VERSION 5.7 ;
  NOWIREEXTENSIONATPIN ON ;
  DIVIDERCHAR "/" ;
  BUSBITCHARS "[]" ;
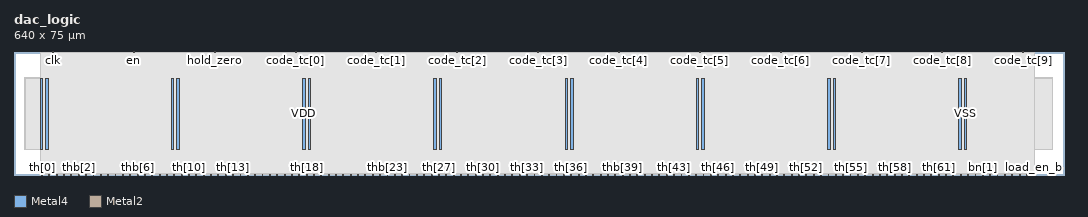
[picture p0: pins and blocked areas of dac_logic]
MACRO dac_logic
  CLASS BLOCK ;
  FOREIGN dac_logic ;
  ORIGIN 0.000 0.000 ;
  SIZE 640.000 BY 75.000 ;
  PIN VDD
    DIRECTION INOUT ;
    USE POWER ;
    PORT
      LAYER Metal4 ;
        RECT 15.920 15.380 17.520 59.100 ;
    END
    PORT
      LAYER Metal4 ;
        RECT 95.920 15.380 97.520 59.100 ;
    END
    PORT
      LAYER Metal4 ;
        RECT 175.920 15.380 177.520 59.100 ;
    END
    PORT
      LAYER Metal4 ;
        RECT 255.920 15.380 257.520 59.100 ;
    END
    PORT
      LAYER Metal4 ;
        RECT 335.920 15.380 337.520 59.100 ;
    END
    PORT
      LAYER Metal4 ;
        RECT 415.920 15.380 417.520 59.100 ;
    END
    PORT
      LAYER Metal4 ;
        RECT 495.920 15.380 497.520 59.100 ;
    END
    PORT
      LAYER Metal4 ;
        RECT 575.920 15.380 577.520 59.100 ;
    END
  END VDD
  PIN VSS
    DIRECTION INOUT ;
    USE GROUND ;
    PORT
      LAYER Metal4 ;
        RECT 19.220 15.380 20.820 59.100 ;
    END
    PORT
      LAYER Metal4 ;
        RECT 99.220 15.380 100.820 59.100 ;
    END
    PORT
      LAYER Metal4 ;
        RECT 179.220 15.380 180.820 59.100 ;
    END
    PORT
      LAYER Metal4 ;
        RECT 259.220 15.380 260.820 59.100 ;
    END
    PORT
      LAYER Metal4 ;
        RECT 339.220 15.380 340.820 59.100 ;
    END
    PORT
      LAYER Metal4 ;
        RECT 419.220 15.380 420.820 59.100 ;
    END
    PORT
      LAYER Metal4 ;
        RECT 499.220 15.380 500.820 59.100 ;
    END
    PORT
      LAYER Metal4 ;
        RECT 579.220 15.380 580.820 59.100 ;
    END
  END VSS
  PIN bn[0]
    DIRECTION OUTPUT ;
    USE SIGNAL ;
    ANTENNAGATEAREA 0.898000 ;
    ANTENNADIFFAREA 0.893200 ;
    PORT
      LAYER Metal2 ;
        RECT 581.280 0.000 581.840 0.560 ;
    END
  END bn[0]
  PIN bn[1]
    DIRECTION OUTPUT ;
    USE SIGNAL ;
    ANTENNAGATEAREA 0.898000 ;
    ANTENNADIFFAREA 0.893200 ;
    PORT
      LAYER Metal2 ;
        RECT 590.240 0.000 590.800 0.560 ;
    END
  END bn[1]
  PIN bn[2]
    DIRECTION OUTPUT ;
    USE SIGNAL ;
    ANTENNAGATEAREA 0.898000 ;
    ANTENNADIFFAREA 0.893200 ;
    PORT
      LAYER Metal2 ;
        RECT 599.200 0.000 599.760 0.560 ;
    END
  END bn[2]
  PIN bn[3]
    DIRECTION OUTPUT ;
    USE SIGNAL ;
    ANTENNAGATEAREA 0.898000 ;
    ANTENNADIFFAREA 0.893200 ;
    PORT
      LAYER Metal2 ;
        RECT 608.160 0.000 608.720 0.560 ;
    END
  END bn[3]
  PIN bnb[0]
    DIRECTION OUTPUT ;
    USE SIGNAL ;
    ANTENNADIFFAREA 0.748000 ;
    PORT
      LAYER Metal2 ;
        RECT 585.760 0.000 586.320 0.560 ;
    END
  END bnb[0]
  PIN bnb[1]
    DIRECTION OUTPUT ;
    USE SIGNAL ;
    ANTENNADIFFAREA 0.748000 ;
    PORT
      LAYER Metal2 ;
        RECT 594.720 0.000 595.280 0.560 ;
    END
  END bnb[1]
  PIN bnb[2]
    DIRECTION OUTPUT ;
    USE SIGNAL ;
    ANTENNADIFFAREA 0.748000 ;
    PORT
      LAYER Metal2 ;
        RECT 603.680 0.000 604.240 0.560 ;
    END
  END bnb[2]
  PIN bnb[3]
    DIRECTION OUTPUT ;
    USE SIGNAL ;
    ANTENNADIFFAREA 0.748000 ;
    PORT
      LAYER Metal2 ;
        RECT 612.640 0.000 613.200 0.560 ;
    END
  END bnb[3]
  PIN clk
    DIRECTION INPUT ;
    USE SIGNAL ;
    ANTENNAGATEAREA 4.738000 ;
    PORT
      LAYER Metal2 ;
        RECT 23.520 74.440 24.080 75.000 ;
    END
  END clk
  PIN code_tc[0]
    DIRECTION INPUT ;
    USE SIGNAL ;
    ANTENNAGATEAREA 0.519000 ;
    ANTENNADIFFAREA 0.410400 ;
    PORT
      LAYER Metal2 ;
        RECT 171.360 74.440 171.920 75.000 ;
    END
  END code_tc[0]
  PIN code_tc[1]
    DIRECTION INPUT ;
    USE SIGNAL ;
    ANTENNAGATEAREA 0.519000 ;
    ANTENNADIFFAREA 0.410400 ;
    PORT
      LAYER Metal2 ;
        RECT 220.640 74.440 221.200 75.000 ;
    END
  END code_tc[1]
  PIN code_tc[2]
    DIRECTION INPUT ;
    USE SIGNAL ;
    ANTENNAGATEAREA 0.519000 ;
    PORT
      LAYER Metal2 ;
        RECT 269.920 74.440 270.480 75.000 ;
    END
  END code_tc[2]
  PIN code_tc[3]
    DIRECTION INPUT ;
    USE SIGNAL ;
    ANTENNAGATEAREA 0.519000 ;
    PORT
      LAYER Metal2 ;
        RECT 319.200 74.440 319.760 75.000 ;
    END
  END code_tc[3]
  PIN code_tc[4]
    DIRECTION INPUT ;
    USE SIGNAL ;
    ANTENNAGATEAREA 0.519000 ;
    PORT
      LAYER Metal2 ;
        RECT 368.480 74.440 369.040 75.000 ;
    END
  END code_tc[4]
  PIN code_tc[5]
    DIRECTION INPUT ;
    USE SIGNAL ;
    ANTENNAGATEAREA 0.519000 ;
    PORT
      LAYER Metal2 ;
        RECT 417.760 74.440 418.320 75.000 ;
    END
  END code_tc[5]
  PIN code_tc[6]
    DIRECTION INPUT ;
    USE SIGNAL ;
    ANTENNAGATEAREA 0.519000 ;
    PORT
      LAYER Metal2 ;
        RECT 467.040 74.440 467.600 75.000 ;
    END
  END code_tc[6]
  PIN code_tc[7]
    DIRECTION INPUT ;
    USE SIGNAL ;
    ANTENNAGATEAREA 0.519000 ;
    PORT
      LAYER Metal2 ;
        RECT 516.320 74.440 516.880 75.000 ;
    END
  END code_tc[7]
  PIN code_tc[8]
    DIRECTION INPUT ;
    USE SIGNAL ;
    ANTENNAGATEAREA 0.519000 ;
    PORT
      LAYER Metal2 ;
        RECT 565.600 74.440 566.160 75.000 ;
    END
  END code_tc[8]
  PIN code_tc[9]
    DIRECTION INPUT ;
    USE SIGNAL ;
    ANTENNAGATEAREA 1.057000 ;
    PORT
      LAYER Metal2 ;
        RECT 614.880 74.440 615.440 75.000 ;
    END
  END code_tc[9]
  PIN en
    DIRECTION INPUT ;
    USE SIGNAL ;
    ANTENNAGATEAREA 103.009995 ;
    PORT
      LAYER Metal2 ;
        RECT 72.800 74.440 73.360 75.000 ;
    END
  END en
  PIN hold_zero
    DIRECTION INPUT ;
    USE SIGNAL ;
    ANTENNAGATEAREA 0.898000 ;
    PORT
      LAYER Metal2 ;
        RECT 122.080 74.440 122.640 75.000 ;
    END
  END hold_zero
  PIN load_en_b
    DIRECTION OUTPUT ;
    USE SIGNAL ;
    ANTENNADIFFAREA 0.748000 ;
    PORT
      LAYER Metal2 ;
        RECT 621.600 0.000 622.160 0.560 ;
    END
  END load_en_b
  PIN out_en
    DIRECTION OUTPUT ;
    USE SIGNAL ;
    ANTENNADIFFAREA 0.897600 ;
    PORT
      LAYER Metal2 ;
        RECT 617.120 0.000 617.680 0.560 ;
    END
  END out_en
  PIN th[0]
    DIRECTION OUTPUT ;
    USE SIGNAL ;
    ANTENNAGATEAREA 0.898000 ;
    ANTENNADIFFAREA 0.893200 ;
    PORT
      LAYER Metal2 ;
        RECT 16.800 0.000 17.360 0.560 ;
    END
  END th[0]
  PIN th[10]
    DIRECTION OUTPUT ;
    USE SIGNAL ;
    ANTENNAGATEAREA 0.898000 ;
    ANTENNADIFFAREA 0.893200 ;
    PORT
      LAYER Metal2 ;
        RECT 106.400 0.000 106.960 0.560 ;
    END
  END th[10]
  PIN th[11]
    DIRECTION OUTPUT ;
    USE SIGNAL ;
    ANTENNAGATEAREA 0.898000 ;
    ANTENNADIFFAREA 0.893200 ;
    PORT
      LAYER Metal2 ;
        RECT 115.360 0.000 115.920 0.560 ;
    END
  END th[11]
  PIN th[12]
    DIRECTION OUTPUT ;
    USE SIGNAL ;
    ANTENNAGATEAREA 0.898000 ;
    ANTENNADIFFAREA 0.893200 ;
    PORT
      LAYER Metal2 ;
        RECT 124.320 0.000 124.880 0.560 ;
    END
  END th[12]
  PIN th[13]
    DIRECTION OUTPUT ;
    USE SIGNAL ;
    ANTENNAGATEAREA 0.898000 ;
    ANTENNADIFFAREA 0.893200 ;
    PORT
      LAYER Metal2 ;
        RECT 133.280 0.000 133.840 0.560 ;
    END
  END th[13]
  PIN th[14]
    DIRECTION OUTPUT ;
    USE SIGNAL ;
    ANTENNAGATEAREA 0.898000 ;
    ANTENNADIFFAREA 0.893200 ;
    PORT
      LAYER Metal2 ;
        RECT 142.240 0.000 142.800 0.560 ;
    END
  END th[14]
  PIN th[15]
    DIRECTION OUTPUT ;
    USE SIGNAL ;
    ANTENNAGATEAREA 0.898000 ;
    ANTENNADIFFAREA 0.893200 ;
    PORT
      LAYER Metal2 ;
        RECT 151.200 0.000 151.760 0.560 ;
    END
  END th[15]
  PIN th[16]
    DIRECTION OUTPUT ;
    USE SIGNAL ;
    ANTENNAGATEAREA 0.898000 ;
    ANTENNADIFFAREA 0.893200 ;
    PORT
      LAYER Metal2 ;
        RECT 160.160 0.000 160.720 0.560 ;
    END
  END th[16]
  PIN th[17]
    DIRECTION OUTPUT ;
    USE SIGNAL ;
    ANTENNAGATEAREA 0.898000 ;
    ANTENNADIFFAREA 0.893200 ;
    PORT
      LAYER Metal2 ;
        RECT 169.120 0.000 169.680 0.560 ;
    END
  END th[17]
  PIN th[18]
    DIRECTION OUTPUT ;
    USE SIGNAL ;
    ANTENNAGATEAREA 0.898000 ;
    ANTENNADIFFAREA 0.893200 ;
    PORT
      LAYER Metal2 ;
        RECT 178.080 0.000 178.640 0.560 ;
    END
  END th[18]
  PIN th[19]
    DIRECTION OUTPUT ;
    USE SIGNAL ;
    ANTENNAGATEAREA 0.898000 ;
    ANTENNADIFFAREA 0.893200 ;
    PORT
      LAYER Metal2 ;
        RECT 187.040 0.000 187.600 0.560 ;
    END
  END th[19]
  PIN th[1]
    DIRECTION OUTPUT ;
    USE SIGNAL ;
    ANTENNAGATEAREA 0.898000 ;
    ANTENNADIFFAREA 0.893200 ;
    PORT
      LAYER Metal2 ;
        RECT 25.760 0.000 26.320 0.560 ;
    END
  END th[1]
  PIN th[20]
    DIRECTION OUTPUT ;
    USE SIGNAL ;
    ANTENNAGATEAREA 0.898000 ;
    ANTENNADIFFAREA 0.893200 ;
    PORT
      LAYER Metal2 ;
        RECT 196.000 0.000 196.560 0.560 ;
    END
  END th[20]
  PIN th[21]
    DIRECTION OUTPUT ;
    USE SIGNAL ;
    ANTENNAGATEAREA 0.898000 ;
    ANTENNADIFFAREA 0.893200 ;
    PORT
      LAYER Metal2 ;
        RECT 204.960 0.000 205.520 0.560 ;
    END
  END th[21]
  PIN th[22]
    DIRECTION OUTPUT ;
    USE SIGNAL ;
    ANTENNAGATEAREA 0.898000 ;
    ANTENNADIFFAREA 0.893200 ;
    PORT
      LAYER Metal2 ;
        RECT 213.920 0.000 214.480 0.560 ;
    END
  END th[22]
  PIN th[23]
    DIRECTION OUTPUT ;
    USE SIGNAL ;
    ANTENNAGATEAREA 0.898000 ;
    ANTENNADIFFAREA 0.893200 ;
    PORT
      LAYER Metal2 ;
        RECT 222.880 0.000 223.440 0.560 ;
    END
  END th[23]
  PIN th[24]
    DIRECTION OUTPUT ;
    USE SIGNAL ;
    ANTENNAGATEAREA 0.898000 ;
    ANTENNADIFFAREA 0.893200 ;
    PORT
      LAYER Metal2 ;
        RECT 231.840 0.000 232.400 0.560 ;
    END
  END th[24]
  PIN th[25]
    DIRECTION OUTPUT ;
    USE SIGNAL ;
    ANTENNAGATEAREA 0.898000 ;
    ANTENNADIFFAREA 0.893200 ;
    PORT
      LAYER Metal2 ;
        RECT 240.800 0.000 241.360 0.560 ;
    END
  END th[25]
  PIN th[26]
    DIRECTION OUTPUT ;
    USE SIGNAL ;
    ANTENNAGATEAREA 0.898000 ;
    ANTENNADIFFAREA 0.893200 ;
    PORT
      LAYER Metal2 ;
        RECT 249.760 0.000 250.320 0.560 ;
    END
  END th[26]
  PIN th[27]
    DIRECTION OUTPUT ;
    USE SIGNAL ;
    ANTENNAGATEAREA 0.898000 ;
    ANTENNADIFFAREA 0.893200 ;
    PORT
      LAYER Metal2 ;
        RECT 258.720 0.000 259.280 0.560 ;
    END
  END th[27]
  PIN th[28]
    DIRECTION OUTPUT ;
    USE SIGNAL ;
    ANTENNAGATEAREA 0.898000 ;
    ANTENNADIFFAREA 0.893200 ;
    PORT
      LAYER Metal2 ;
        RECT 267.680 0.000 268.240 0.560 ;
    END
  END th[28]
  PIN th[29]
    DIRECTION OUTPUT ;
    USE SIGNAL ;
    ANTENNAGATEAREA 0.898000 ;
    ANTENNADIFFAREA 0.893200 ;
    PORT
      LAYER Metal2 ;
        RECT 276.640 0.000 277.200 0.560 ;
    END
  END th[29]
  PIN th[2]
    DIRECTION OUTPUT ;
    USE SIGNAL ;
    ANTENNAGATEAREA 0.898000 ;
    ANTENNADIFFAREA 0.893200 ;
    PORT
      LAYER Metal2 ;
        RECT 34.720 0.000 35.280 0.560 ;
    END
  END th[2]
  PIN th[30]
    DIRECTION OUTPUT ;
    USE SIGNAL ;
    ANTENNAGATEAREA 0.898000 ;
    ANTENNADIFFAREA 0.893200 ;
    PORT
      LAYER Metal2 ;
        RECT 285.600 0.000 286.160 0.560 ;
    END
  END th[30]
  PIN th[31]
    DIRECTION OUTPUT ;
    USE SIGNAL ;
    ANTENNAGATEAREA 0.898000 ;
    ANTENNADIFFAREA 0.893200 ;
    PORT
      LAYER Metal2 ;
        RECT 294.560 0.000 295.120 0.560 ;
    END
  END th[31]
  PIN th[32]
    DIRECTION OUTPUT ;
    USE SIGNAL ;
    ANTENNAGATEAREA 0.898000 ;
    ANTENNADIFFAREA 0.893200 ;
    PORT
      LAYER Metal2 ;
        RECT 303.520 0.000 304.080 0.560 ;
    END
  END th[32]
  PIN th[33]
    DIRECTION OUTPUT ;
    USE SIGNAL ;
    ANTENNAGATEAREA 0.898000 ;
    ANTENNADIFFAREA 0.893200 ;
    PORT
      LAYER Metal2 ;
        RECT 312.480 0.000 313.040 0.560 ;
    END
  END th[33]
  PIN th[34]
    DIRECTION OUTPUT ;
    USE SIGNAL ;
    ANTENNAGATEAREA 0.898000 ;
    ANTENNADIFFAREA 0.893200 ;
    PORT
      LAYER Metal2 ;
        RECT 321.440 0.000 322.000 0.560 ;
    END
  END th[34]
  PIN th[35]
    DIRECTION OUTPUT ;
    USE SIGNAL ;
    ANTENNAGATEAREA 0.898000 ;
    ANTENNADIFFAREA 0.893200 ;
    PORT
      LAYER Metal2 ;
        RECT 330.400 0.000 330.960 0.560 ;
    END
  END th[35]
  PIN th[36]
    DIRECTION OUTPUT ;
    USE SIGNAL ;
    ANTENNAGATEAREA 0.898000 ;
    ANTENNADIFFAREA 0.893200 ;
    PORT
      LAYER Metal2 ;
        RECT 339.360 0.000 339.920 0.560 ;
    END
  END th[36]
  PIN th[37]
    DIRECTION OUTPUT ;
    USE SIGNAL ;
    ANTENNAGATEAREA 0.898000 ;
    ANTENNADIFFAREA 0.893200 ;
    PORT
      LAYER Metal2 ;
        RECT 348.320 0.000 348.880 0.560 ;
    END
  END th[37]
  PIN th[38]
    DIRECTION OUTPUT ;
    USE SIGNAL ;
    ANTENNAGATEAREA 0.898000 ;
    ANTENNADIFFAREA 0.893200 ;
    PORT
      LAYER Metal2 ;
        RECT 357.280 0.000 357.840 0.560 ;
    END
  END th[38]
  PIN th[39]
    DIRECTION OUTPUT ;
    USE SIGNAL ;
    ANTENNAGATEAREA 0.898000 ;
    ANTENNADIFFAREA 0.893200 ;
    PORT
      LAYER Metal2 ;
        RECT 366.240 0.000 366.800 0.560 ;
    END
  END th[39]
  PIN th[3]
    DIRECTION OUTPUT ;
    USE SIGNAL ;
    ANTENNAGATEAREA 0.898000 ;
    ANTENNADIFFAREA 0.893200 ;
    PORT
      LAYER Metal2 ;
        RECT 43.680 0.000 44.240 0.560 ;
    END
  END th[3]
  PIN th[40]
    DIRECTION OUTPUT ;
    USE SIGNAL ;
    ANTENNAGATEAREA 0.898000 ;
    ANTENNADIFFAREA 0.893200 ;
    PORT
      LAYER Metal2 ;
        RECT 375.200 0.000 375.760 0.560 ;
    END
  END th[40]
  PIN th[41]
    DIRECTION OUTPUT ;
    USE SIGNAL ;
    ANTENNAGATEAREA 0.898000 ;
    ANTENNADIFFAREA 0.893200 ;
    PORT
      LAYER Metal2 ;
        RECT 384.160 0.000 384.720 0.560 ;
    END
  END th[41]
  PIN th[42]
    DIRECTION OUTPUT ;
    USE SIGNAL ;
    ANTENNAGATEAREA 0.898000 ;
    ANTENNADIFFAREA 0.893200 ;
    PORT
      LAYER Metal2 ;
        RECT 393.120 0.000 393.680 0.560 ;
    END
  END th[42]
  PIN th[43]
    DIRECTION OUTPUT ;
    USE SIGNAL ;
    ANTENNAGATEAREA 0.898000 ;
    ANTENNADIFFAREA 0.893200 ;
    PORT
      LAYER Metal2 ;
        RECT 402.080 0.000 402.640 0.560 ;
    END
  END th[43]
  PIN th[44]
    DIRECTION OUTPUT ;
    USE SIGNAL ;
    ANTENNAGATEAREA 0.898000 ;
    ANTENNADIFFAREA 0.893200 ;
    PORT
      LAYER Metal2 ;
        RECT 411.040 0.000 411.600 0.560 ;
    END
  END th[44]
  PIN th[45]
    DIRECTION OUTPUT ;
    USE SIGNAL ;
    ANTENNAGATEAREA 0.898000 ;
    ANTENNADIFFAREA 0.893200 ;
    PORT
      LAYER Metal2 ;
        RECT 420.000 0.000 420.560 0.560 ;
    END
  END th[45]
  PIN th[46]
    DIRECTION OUTPUT ;
    USE SIGNAL ;
    ANTENNAGATEAREA 0.898000 ;
    ANTENNADIFFAREA 0.893200 ;
    PORT
      LAYER Metal2 ;
        RECT 428.960 0.000 429.520 0.560 ;
    END
  END th[46]
  PIN th[47]
    DIRECTION OUTPUT ;
    USE SIGNAL ;
    ANTENNAGATEAREA 0.898000 ;
    ANTENNADIFFAREA 0.893200 ;
    PORT
      LAYER Metal2 ;
        RECT 437.920 0.000 438.480 0.560 ;
    END
  END th[47]
  PIN th[48]
    DIRECTION OUTPUT ;
    USE SIGNAL ;
    ANTENNAGATEAREA 0.898000 ;
    ANTENNADIFFAREA 0.893200 ;
    PORT
      LAYER Metal2 ;
        RECT 446.880 0.000 447.440 0.560 ;
    END
  END th[48]
  PIN th[49]
    DIRECTION OUTPUT ;
    USE SIGNAL ;
    ANTENNAGATEAREA 0.898000 ;
    ANTENNADIFFAREA 0.893200 ;
    PORT
      LAYER Metal2 ;
        RECT 455.840 0.000 456.400 0.560 ;
    END
  END th[49]
  PIN th[4]
    DIRECTION OUTPUT ;
    USE SIGNAL ;
    ANTENNAGATEAREA 0.898000 ;
    ANTENNADIFFAREA 0.893200 ;
    PORT
      LAYER Metal2 ;
        RECT 52.640 0.000 53.200 0.560 ;
    END
  END th[4]
  PIN th[50]
    DIRECTION OUTPUT ;
    USE SIGNAL ;
    ANTENNAGATEAREA 0.898000 ;
    ANTENNADIFFAREA 0.893200 ;
    PORT
      LAYER Metal2 ;
        RECT 464.800 0.000 465.360 0.560 ;
    END
  END th[50]
  PIN th[51]
    DIRECTION OUTPUT ;
    USE SIGNAL ;
    ANTENNAGATEAREA 0.898000 ;
    ANTENNADIFFAREA 0.893200 ;
    PORT
      LAYER Metal2 ;
        RECT 473.760 0.000 474.320 0.560 ;
    END
  END th[51]
  PIN th[52]
    DIRECTION OUTPUT ;
    USE SIGNAL ;
    ANTENNAGATEAREA 0.898000 ;
    ANTENNADIFFAREA 0.893200 ;
    PORT
      LAYER Metal2 ;
        RECT 482.720 0.000 483.280 0.560 ;
    END
  END th[52]
  PIN th[53]
    DIRECTION OUTPUT ;
    USE SIGNAL ;
    ANTENNAGATEAREA 0.898000 ;
    ANTENNADIFFAREA 0.893200 ;
    PORT
      LAYER Metal2 ;
        RECT 491.680 0.000 492.240 0.560 ;
    END
  END th[53]
  PIN th[54]
    DIRECTION OUTPUT ;
    USE SIGNAL ;
    ANTENNAGATEAREA 0.898000 ;
    ANTENNADIFFAREA 0.893200 ;
    PORT
      LAYER Metal2 ;
        RECT 500.640 0.000 501.200 0.560 ;
    END
  END th[54]
  PIN th[55]
    DIRECTION OUTPUT ;
    USE SIGNAL ;
    ANTENNAGATEAREA 0.898000 ;
    ANTENNADIFFAREA 0.893200 ;
    PORT
      LAYER Metal2 ;
        RECT 509.600 0.000 510.160 0.560 ;
    END
  END th[55]
  PIN th[56]
    DIRECTION OUTPUT ;
    USE SIGNAL ;
    ANTENNAGATEAREA 0.898000 ;
    ANTENNADIFFAREA 0.893200 ;
    PORT
      LAYER Metal2 ;
        RECT 518.560 0.000 519.120 0.560 ;
    END
  END th[56]
  PIN th[57]
    DIRECTION OUTPUT ;
    USE SIGNAL ;
    ANTENNAGATEAREA 0.898000 ;
    ANTENNADIFFAREA 0.893200 ;
    PORT
      LAYER Metal2 ;
        RECT 527.520 0.000 528.080 0.560 ;
    END
  END th[57]
  PIN th[58]
    DIRECTION OUTPUT ;
    USE SIGNAL ;
    ANTENNAGATEAREA 0.898000 ;
    ANTENNADIFFAREA 0.893200 ;
    PORT
      LAYER Metal2 ;
        RECT 536.480 0.000 537.040 0.560 ;
    END
  END th[58]
  PIN th[59]
    DIRECTION OUTPUT ;
    USE SIGNAL ;
    ANTENNAGATEAREA 0.898000 ;
    ANTENNADIFFAREA 0.893200 ;
    PORT
      LAYER Metal2 ;
        RECT 545.440 0.000 546.000 0.560 ;
    END
  END th[59]
  PIN th[5]
    DIRECTION OUTPUT ;
    USE SIGNAL ;
    ANTENNAGATEAREA 0.898000 ;
    ANTENNADIFFAREA 0.893200 ;
    PORT
      LAYER Metal2 ;
        RECT 61.600 0.000 62.160 0.560 ;
    END
  END th[5]
  PIN th[60]
    DIRECTION OUTPUT ;
    USE SIGNAL ;
    ANTENNAGATEAREA 0.898000 ;
    ANTENNADIFFAREA 0.893200 ;
    PORT
      LAYER Metal2 ;
        RECT 554.400 0.000 554.960 0.560 ;
    END
  END th[60]
  PIN th[61]
    DIRECTION OUTPUT ;
    USE SIGNAL ;
    ANTENNAGATEAREA 0.898000 ;
    ANTENNADIFFAREA 0.893200 ;
    PORT
      LAYER Metal2 ;
        RECT 563.360 0.000 563.920 0.560 ;
    END
  END th[61]
  PIN th[62]
    DIRECTION OUTPUT ;
    USE SIGNAL ;
    ANTENNAGATEAREA 0.898000 ;
    ANTENNADIFFAREA 0.893200 ;
    PORT
      LAYER Metal2 ;
        RECT 572.320 0.000 572.880 0.560 ;
    END
  END th[62]
  PIN th[6]
    DIRECTION OUTPUT ;
    USE SIGNAL ;
    ANTENNAGATEAREA 0.898000 ;
    ANTENNADIFFAREA 0.893200 ;
    PORT
      LAYER Metal2 ;
        RECT 70.560 0.000 71.120 0.560 ;
    END
  END th[6]
  PIN th[7]
    DIRECTION OUTPUT ;
    USE SIGNAL ;
    ANTENNAGATEAREA 0.898000 ;
    ANTENNADIFFAREA 0.893200 ;
    PORT
      LAYER Metal2 ;
        RECT 79.520 0.000 80.080 0.560 ;
    END
  END th[7]
  PIN th[8]
    DIRECTION OUTPUT ;
    USE SIGNAL ;
    ANTENNAGATEAREA 0.898000 ;
    ANTENNADIFFAREA 0.893200 ;
    PORT
      LAYER Metal2 ;
        RECT 88.480 0.000 89.040 0.560 ;
    END
  END th[8]
  PIN th[9]
    DIRECTION OUTPUT ;
    USE SIGNAL ;
    ANTENNAGATEAREA 0.898000 ;
    ANTENNADIFFAREA 0.893200 ;
    PORT
      LAYER Metal2 ;
        RECT 97.440 0.000 98.000 0.560 ;
    END
  END th[9]
  PIN thb[0]
    DIRECTION OUTPUT ;
    USE SIGNAL ;
    ANTENNADIFFAREA 0.748000 ;
    PORT
      LAYER Metal2 ;
        RECT 21.280 0.000 21.840 0.560 ;
    END
  END thb[0]
  PIN thb[10]
    DIRECTION OUTPUT ;
    USE SIGNAL ;
    ANTENNADIFFAREA 0.748000 ;
    PORT
      LAYER Metal2 ;
        RECT 110.880 0.000 111.440 0.560 ;
    END
  END thb[10]
  PIN thb[11]
    DIRECTION OUTPUT ;
    USE SIGNAL ;
    ANTENNADIFFAREA 0.748000 ;
    PORT
      LAYER Metal2 ;
        RECT 119.840 0.000 120.400 0.560 ;
    END
  END thb[11]
  PIN thb[12]
    DIRECTION OUTPUT ;
    USE SIGNAL ;
    ANTENNADIFFAREA 0.748000 ;
    PORT
      LAYER Metal2 ;
        RECT 128.800 0.000 129.360 0.560 ;
    END
  END thb[12]
  PIN thb[13]
    DIRECTION OUTPUT ;
    USE SIGNAL ;
    ANTENNADIFFAREA 0.748000 ;
    PORT
      LAYER Metal2 ;
        RECT 137.760 0.000 138.320 0.560 ;
    END
  END thb[13]
  PIN thb[14]
    DIRECTION OUTPUT ;
    USE SIGNAL ;
    ANTENNADIFFAREA 0.748000 ;
    PORT
      LAYER Metal2 ;
        RECT 146.720 0.000 147.280 0.560 ;
    END
  END thb[14]
  PIN thb[15]
    DIRECTION OUTPUT ;
    USE SIGNAL ;
    ANTENNADIFFAREA 0.748000 ;
    PORT
      LAYER Metal2 ;
        RECT 155.680 0.000 156.240 0.560 ;
    END
  END thb[15]
  PIN thb[16]
    DIRECTION OUTPUT ;
    USE SIGNAL ;
    ANTENNADIFFAREA 0.748000 ;
    PORT
      LAYER Metal2 ;
        RECT 164.640 0.000 165.200 0.560 ;
    END
  END thb[16]
  PIN thb[17]
    DIRECTION OUTPUT ;
    USE SIGNAL ;
    ANTENNADIFFAREA 0.748000 ;
    PORT
      LAYER Metal2 ;
        RECT 173.600 0.000 174.160 0.560 ;
    END
  END thb[17]
  PIN thb[18]
    DIRECTION OUTPUT ;
    USE SIGNAL ;
    ANTENNADIFFAREA 0.748000 ;
    PORT
      LAYER Metal2 ;
        RECT 182.560 0.000 183.120 0.560 ;
    END
  END thb[18]
  PIN thb[19]
    DIRECTION OUTPUT ;
    USE SIGNAL ;
    ANTENNADIFFAREA 0.748000 ;
    PORT
      LAYER Metal2 ;
        RECT 191.520 0.000 192.080 0.560 ;
    END
  END thb[19]
  PIN thb[1]
    DIRECTION OUTPUT ;
    USE SIGNAL ;
    ANTENNADIFFAREA 0.748000 ;
    PORT
      LAYER Metal2 ;
        RECT 30.240 0.000 30.800 0.560 ;
    END
  END thb[1]
  PIN thb[20]
    DIRECTION OUTPUT ;
    USE SIGNAL ;
    ANTENNADIFFAREA 0.748000 ;
    PORT
      LAYER Metal2 ;
        RECT 200.480 0.000 201.040 0.560 ;
    END
  END thb[20]
  PIN thb[21]
    DIRECTION OUTPUT ;
    USE SIGNAL ;
    ANTENNADIFFAREA 0.748000 ;
    PORT
      LAYER Metal2 ;
        RECT 209.440 0.000 210.000 0.560 ;
    END
  END thb[21]
  PIN thb[22]
    DIRECTION OUTPUT ;
    USE SIGNAL ;
    ANTENNADIFFAREA 0.748000 ;
    PORT
      LAYER Metal2 ;
        RECT 218.400 0.000 218.960 0.560 ;
    END
  END thb[22]
  PIN thb[23]
    DIRECTION OUTPUT ;
    USE SIGNAL ;
    ANTENNADIFFAREA 0.748000 ;
    PORT
      LAYER Metal2 ;
        RECT 227.360 0.000 227.920 0.560 ;
    END
  END thb[23]
  PIN thb[24]
    DIRECTION OUTPUT ;
    USE SIGNAL ;
    ANTENNADIFFAREA 0.748000 ;
    PORT
      LAYER Metal2 ;
        RECT 236.320 0.000 236.880 0.560 ;
    END
  END thb[24]
  PIN thb[25]
    DIRECTION OUTPUT ;
    USE SIGNAL ;
    ANTENNADIFFAREA 0.748000 ;
    PORT
      LAYER Metal2 ;
        RECT 245.280 0.000 245.840 0.560 ;
    END
  END thb[25]
  PIN thb[26]
    DIRECTION OUTPUT ;
    USE SIGNAL ;
    ANTENNADIFFAREA 0.748000 ;
    PORT
      LAYER Metal2 ;
        RECT 254.240 0.000 254.800 0.560 ;
    END
  END thb[26]
  PIN thb[27]
    DIRECTION OUTPUT ;
    USE SIGNAL ;
    ANTENNADIFFAREA 0.748000 ;
    PORT
      LAYER Metal2 ;
        RECT 263.200 0.000 263.760 0.560 ;
    END
  END thb[27]
  PIN thb[28]
    DIRECTION OUTPUT ;
    USE SIGNAL ;
    ANTENNADIFFAREA 0.748000 ;
    PORT
      LAYER Metal2 ;
        RECT 272.160 0.000 272.720 0.560 ;
    END
  END thb[28]
  PIN thb[29]
    DIRECTION OUTPUT ;
    USE SIGNAL ;
    ANTENNADIFFAREA 0.748000 ;
    PORT
      LAYER Metal2 ;
        RECT 281.120 0.000 281.680 0.560 ;
    END
  END thb[29]
  PIN thb[2]
    DIRECTION OUTPUT ;
    USE SIGNAL ;
    ANTENNADIFFAREA 0.748000 ;
    PORT
      LAYER Metal2 ;
        RECT 39.200 0.000 39.760 0.560 ;
    END
  END thb[2]
  PIN thb[30]
    DIRECTION OUTPUT ;
    USE SIGNAL ;
    ANTENNADIFFAREA 0.748000 ;
    PORT
      LAYER Metal2 ;
        RECT 290.080 0.000 290.640 0.560 ;
    END
  END thb[30]
  PIN thb[31]
    DIRECTION OUTPUT ;
    USE SIGNAL ;
    ANTENNADIFFAREA 0.748000 ;
    PORT
      LAYER Metal2 ;
        RECT 299.040 0.000 299.600 0.560 ;
    END
  END thb[31]
  PIN thb[32]
    DIRECTION OUTPUT ;
    USE SIGNAL ;
    ANTENNADIFFAREA 0.748000 ;
    PORT
      LAYER Metal2 ;
        RECT 308.000 0.000 308.560 0.560 ;
    END
  END thb[32]
  PIN thb[33]
    DIRECTION OUTPUT ;
    USE SIGNAL ;
    ANTENNADIFFAREA 0.748000 ;
    PORT
      LAYER Metal2 ;
        RECT 316.960 0.000 317.520 0.560 ;
    END
  END thb[33]
  PIN thb[34]
    DIRECTION OUTPUT ;
    USE SIGNAL ;
    ANTENNADIFFAREA 0.748000 ;
    PORT
      LAYER Metal2 ;
        RECT 325.920 0.000 326.480 0.560 ;
    END
  END thb[34]
  PIN thb[35]
    DIRECTION OUTPUT ;
    USE SIGNAL ;
    ANTENNADIFFAREA 0.748000 ;
    PORT
      LAYER Metal2 ;
        RECT 334.880 0.000 335.440 0.560 ;
    END
  END thb[35]
  PIN thb[36]
    DIRECTION OUTPUT ;
    USE SIGNAL ;
    ANTENNADIFFAREA 0.748000 ;
    PORT
      LAYER Metal2 ;
        RECT 343.840 0.000 344.400 0.560 ;
    END
  END thb[36]
  PIN thb[37]
    DIRECTION OUTPUT ;
    USE SIGNAL ;
    ANTENNADIFFAREA 0.748000 ;
    PORT
      LAYER Metal2 ;
        RECT 352.800 0.000 353.360 0.560 ;
    END
  END thb[37]
  PIN thb[38]
    DIRECTION OUTPUT ;
    USE SIGNAL ;
    ANTENNADIFFAREA 0.748000 ;
    PORT
      LAYER Metal2 ;
        RECT 361.760 0.000 362.320 0.560 ;
    END
  END thb[38]
  PIN thb[39]
    DIRECTION OUTPUT ;
    USE SIGNAL ;
    ANTENNADIFFAREA 0.748000 ;
    PORT
      LAYER Metal2 ;
        RECT 370.720 0.000 371.280 0.560 ;
    END
  END thb[39]
  PIN thb[3]
    DIRECTION OUTPUT ;
    USE SIGNAL ;
    ANTENNADIFFAREA 0.748000 ;
    PORT
      LAYER Metal2 ;
        RECT 48.160 0.000 48.720 0.560 ;
    END
  END thb[3]
  PIN thb[40]
    DIRECTION OUTPUT ;
    USE SIGNAL ;
    ANTENNADIFFAREA 0.748000 ;
    PORT
      LAYER Metal2 ;
        RECT 379.680 0.000 380.240 0.560 ;
    END
  END thb[40]
  PIN thb[41]
    DIRECTION OUTPUT ;
    USE SIGNAL ;
    ANTENNADIFFAREA 0.748000 ;
    PORT
      LAYER Metal2 ;
        RECT 388.640 0.000 389.200 0.560 ;
    END
  END thb[41]
  PIN thb[42]
    DIRECTION OUTPUT ;
    USE SIGNAL ;
    ANTENNADIFFAREA 0.748000 ;
    PORT
      LAYER Metal2 ;
        RECT 397.600 0.000 398.160 0.560 ;
    END
  END thb[42]
  PIN thb[43]
    DIRECTION OUTPUT ;
    USE SIGNAL ;
    ANTENNADIFFAREA 0.748000 ;
    PORT
      LAYER Metal2 ;
        RECT 406.560 0.000 407.120 0.560 ;
    END
  END thb[43]
  PIN thb[44]
    DIRECTION OUTPUT ;
    USE SIGNAL ;
    ANTENNADIFFAREA 0.748000 ;
    PORT
      LAYER Metal2 ;
        RECT 415.520 0.000 416.080 0.560 ;
    END
  END thb[44]
  PIN thb[45]
    DIRECTION OUTPUT ;
    USE SIGNAL ;
    ANTENNADIFFAREA 0.748000 ;
    PORT
      LAYER Metal2 ;
        RECT 424.480 0.000 425.040 0.560 ;
    END
  END thb[45]
  PIN thb[46]
    DIRECTION OUTPUT ;
    USE SIGNAL ;
    ANTENNADIFFAREA 0.748000 ;
    PORT
      LAYER Metal2 ;
        RECT 433.440 0.000 434.000 0.560 ;
    END
  END thb[46]
  PIN thb[47]
    DIRECTION OUTPUT ;
    USE SIGNAL ;
    ANTENNADIFFAREA 0.748000 ;
    PORT
      LAYER Metal2 ;
        RECT 442.400 0.000 442.960 0.560 ;
    END
  END thb[47]
  PIN thb[48]
    DIRECTION OUTPUT ;
    USE SIGNAL ;
    ANTENNADIFFAREA 0.748000 ;
    PORT
      LAYER Metal2 ;
        RECT 451.360 0.000 451.920 0.560 ;
    END
  END thb[48]
  PIN thb[49]
    DIRECTION OUTPUT ;
    USE SIGNAL ;
    ANTENNADIFFAREA 0.748000 ;
    PORT
      LAYER Metal2 ;
        RECT 460.320 0.000 460.880 0.560 ;
    END
  END thb[49]
  PIN thb[4]
    DIRECTION OUTPUT ;
    USE SIGNAL ;
    ANTENNADIFFAREA 0.748000 ;
    PORT
      LAYER Metal2 ;
        RECT 57.120 0.000 57.680 0.560 ;
    END
  END thb[4]
  PIN thb[50]
    DIRECTION OUTPUT ;
    USE SIGNAL ;
    ANTENNADIFFAREA 0.748000 ;
    PORT
      LAYER Metal2 ;
        RECT 469.280 0.000 469.840 0.560 ;
    END
  END thb[50]
  PIN thb[51]
    DIRECTION OUTPUT ;
    USE SIGNAL ;
    ANTENNADIFFAREA 0.748000 ;
    PORT
      LAYER Metal2 ;
        RECT 478.240 0.000 478.800 0.560 ;
    END
  END thb[51]
  PIN thb[52]
    DIRECTION OUTPUT ;
    USE SIGNAL ;
    ANTENNADIFFAREA 0.748000 ;
    PORT
      LAYER Metal2 ;
        RECT 487.200 0.000 487.760 0.560 ;
    END
  END thb[52]
  PIN thb[53]
    DIRECTION OUTPUT ;
    USE SIGNAL ;
    ANTENNADIFFAREA 0.748000 ;
    PORT
      LAYER Metal2 ;
        RECT 496.160 0.000 496.720 0.560 ;
    END
  END thb[53]
  PIN thb[54]
    DIRECTION OUTPUT ;
    USE SIGNAL ;
    ANTENNADIFFAREA 0.748000 ;
    PORT
      LAYER Metal2 ;
        RECT 505.120 0.000 505.680 0.560 ;
    END
  END thb[54]
  PIN thb[55]
    DIRECTION OUTPUT ;
    USE SIGNAL ;
    ANTENNADIFFAREA 0.748000 ;
    PORT
      LAYER Metal2 ;
        RECT 514.080 0.000 514.640 0.560 ;
    END
  END thb[55]
  PIN thb[56]
    DIRECTION OUTPUT ;
    USE SIGNAL ;
    ANTENNADIFFAREA 0.748000 ;
    PORT
      LAYER Metal2 ;
        RECT 523.040 0.000 523.600 0.560 ;
    END
  END thb[56]
  PIN thb[57]
    DIRECTION OUTPUT ;
    USE SIGNAL ;
    ANTENNADIFFAREA 0.748000 ;
    PORT
      LAYER Metal2 ;
        RECT 532.000 0.000 532.560 0.560 ;
    END
  END thb[57]
  PIN thb[58]
    DIRECTION OUTPUT ;
    USE SIGNAL ;
    ANTENNADIFFAREA 0.748000 ;
    PORT
      LAYER Metal2 ;
        RECT 540.960 0.000 541.520 0.560 ;
    END
  END thb[58]
  PIN thb[59]
    DIRECTION OUTPUT ;
    USE SIGNAL ;
    ANTENNADIFFAREA 0.748000 ;
    PORT
      LAYER Metal2 ;
        RECT 549.920 0.000 550.480 0.560 ;
    END
  END thb[59]
  PIN thb[5]
    DIRECTION OUTPUT ;
    USE SIGNAL ;
    ANTENNADIFFAREA 0.748000 ;
    PORT
      LAYER Metal2 ;
        RECT 66.080 0.000 66.640 0.560 ;
    END
  END thb[5]
  PIN thb[60]
    DIRECTION OUTPUT ;
    USE SIGNAL ;
    ANTENNADIFFAREA 0.748000 ;
    PORT
      LAYER Metal2 ;
        RECT 558.880 0.000 559.440 0.560 ;
    END
  END thb[60]
  PIN thb[61]
    DIRECTION OUTPUT ;
    USE SIGNAL ;
    ANTENNADIFFAREA 0.748000 ;
    PORT
      LAYER Metal2 ;
        RECT 567.840 0.000 568.400 0.560 ;
    END
  END thb[61]
  PIN thb[62]
    DIRECTION OUTPUT ;
    USE SIGNAL ;
    ANTENNADIFFAREA 0.748000 ;
    PORT
      LAYER Metal2 ;
        RECT 576.800 0.000 577.360 0.560 ;
    END
  END thb[62]
  PIN thb[6]
    DIRECTION OUTPUT ;
    USE SIGNAL ;
    ANTENNADIFFAREA 0.748000 ;
    PORT
      LAYER Metal2 ;
        RECT 75.040 0.000 75.600 0.560 ;
    END
  END thb[6]
  PIN thb[7]
    DIRECTION OUTPUT ;
    USE SIGNAL ;
    ANTENNADIFFAREA 0.748000 ;
    PORT
      LAYER Metal2 ;
        RECT 84.000 0.000 84.560 0.560 ;
    END
  END thb[7]
  PIN thb[8]
    DIRECTION OUTPUT ;
    USE SIGNAL ;
    ANTENNADIFFAREA 0.748000 ;
    PORT
      LAYER Metal2 ;
        RECT 92.960 0.000 93.520 0.560 ;
    END
  END thb[8]
  PIN thb[9]
    DIRECTION OUTPUT ;
    USE SIGNAL ;
    ANTENNADIFFAREA 0.748000 ;
    PORT
      LAYER Metal2 ;
        RECT 101.920 0.000 102.480 0.560 ;
    END
  END thb[9]
  OBS
      LAYER Nwell ;
        RECT 6.290 56.640 633.230 59.230 ;
      LAYER Pwell ;
        RECT 6.290 53.120 633.230 56.640 ;
      LAYER Nwell ;
        RECT 6.290 48.800 633.230 53.120 ;
      LAYER Pwell ;
        RECT 6.290 45.280 633.230 48.800 ;
      LAYER Nwell ;
        RECT 6.290 40.960 633.230 45.280 ;
      LAYER Pwell ;
        RECT 6.290 37.440 633.230 40.960 ;
      LAYER Nwell ;
        RECT 6.290 33.120 633.230 37.440 ;
      LAYER Pwell ;
        RECT 6.290 29.600 633.230 33.120 ;
      LAYER Nwell ;
        RECT 6.290 25.280 633.230 29.600 ;
      LAYER Pwell ;
        RECT 6.290 21.760 633.230 25.280 ;
      LAYER Nwell ;
        RECT 6.290 17.440 633.230 21.760 ;
      LAYER Pwell ;
        RECT 6.290 15.250 633.230 17.440 ;
      LAYER Metal1 ;
        RECT 6.720 15.380 632.800 59.100 ;
      LAYER Metal2 ;
        RECT 16.060 74.140 23.220 74.950 ;
        RECT 24.380 74.140 72.500 74.950 ;
        RECT 73.660 74.140 121.780 74.950 ;
        RECT 122.940 74.140 171.060 74.950 ;
        RECT 172.220 74.140 220.340 74.950 ;
        RECT 221.500 74.140 269.620 74.950 ;
        RECT 270.780 74.140 318.900 74.950 ;
        RECT 320.060 74.140 368.180 74.950 ;
        RECT 369.340 74.140 417.460 74.950 ;
        RECT 418.620 74.140 466.740 74.950 ;
        RECT 467.900 74.140 516.020 74.950 ;
        RECT 517.180 74.140 565.300 74.950 ;
        RECT 566.460 74.140 614.580 74.950 ;
        RECT 615.740 74.140 622.020 74.950 ;
        RECT 16.060 0.860 622.020 74.140 ;
        RECT 16.060 0.140 16.500 0.860 ;
        RECT 17.660 0.140 20.980 0.860 ;
        RECT 22.140 0.140 25.460 0.860 ;
        RECT 26.620 0.140 29.940 0.860 ;
        RECT 31.100 0.140 34.420 0.860 ;
        RECT 35.580 0.140 38.900 0.860 ;
        RECT 40.060 0.140 43.380 0.860 ;
        RECT 44.540 0.140 47.860 0.860 ;
        RECT 49.020 0.140 52.340 0.860 ;
        RECT 53.500 0.140 56.820 0.860 ;
        RECT 57.980 0.140 61.300 0.860 ;
        RECT 62.460 0.140 65.780 0.860 ;
        RECT 66.940 0.140 70.260 0.860 ;
        RECT 71.420 0.140 74.740 0.860 ;
        RECT 75.900 0.140 79.220 0.860 ;
        RECT 80.380 0.140 83.700 0.860 ;
        RECT 84.860 0.140 88.180 0.860 ;
        RECT 89.340 0.140 92.660 0.860 ;
        RECT 93.820 0.140 97.140 0.860 ;
        RECT 98.300 0.140 101.620 0.860 ;
        RECT 102.780 0.140 106.100 0.860 ;
        RECT 107.260 0.140 110.580 0.860 ;
        RECT 111.740 0.140 115.060 0.860 ;
        RECT 116.220 0.140 119.540 0.860 ;
        RECT 120.700 0.140 124.020 0.860 ;
        RECT 125.180 0.140 128.500 0.860 ;
        RECT 129.660 0.140 132.980 0.860 ;
        RECT 134.140 0.140 137.460 0.860 ;
        RECT 138.620 0.140 141.940 0.860 ;
        RECT 143.100 0.140 146.420 0.860 ;
        RECT 147.580 0.140 150.900 0.860 ;
        RECT 152.060 0.140 155.380 0.860 ;
        RECT 156.540 0.140 159.860 0.860 ;
        RECT 161.020 0.140 164.340 0.860 ;
        RECT 165.500 0.140 168.820 0.860 ;
        RECT 169.980 0.140 173.300 0.860 ;
        RECT 174.460 0.140 177.780 0.860 ;
        RECT 178.940 0.140 182.260 0.860 ;
        RECT 183.420 0.140 186.740 0.860 ;
        RECT 187.900 0.140 191.220 0.860 ;
        RECT 192.380 0.140 195.700 0.860 ;
        RECT 196.860 0.140 200.180 0.860 ;
        RECT 201.340 0.140 204.660 0.860 ;
        RECT 205.820 0.140 209.140 0.860 ;
        RECT 210.300 0.140 213.620 0.860 ;
        RECT 214.780 0.140 218.100 0.860 ;
        RECT 219.260 0.140 222.580 0.860 ;
        RECT 223.740 0.140 227.060 0.860 ;
        RECT 228.220 0.140 231.540 0.860 ;
        RECT 232.700 0.140 236.020 0.860 ;
        RECT 237.180 0.140 240.500 0.860 ;
        RECT 241.660 0.140 244.980 0.860 ;
        RECT 246.140 0.140 249.460 0.860 ;
        RECT 250.620 0.140 253.940 0.860 ;
        RECT 255.100 0.140 258.420 0.860 ;
        RECT 259.580 0.140 262.900 0.860 ;
        RECT 264.060 0.140 267.380 0.860 ;
        RECT 268.540 0.140 271.860 0.860 ;
        RECT 273.020 0.140 276.340 0.860 ;
        RECT 277.500 0.140 280.820 0.860 ;
        RECT 281.980 0.140 285.300 0.860 ;
        RECT 286.460 0.140 289.780 0.860 ;
        RECT 290.940 0.140 294.260 0.860 ;
        RECT 295.420 0.140 298.740 0.860 ;
        RECT 299.900 0.140 303.220 0.860 ;
        RECT 304.380 0.140 307.700 0.860 ;
        RECT 308.860 0.140 312.180 0.860 ;
        RECT 313.340 0.140 316.660 0.860 ;
        RECT 317.820 0.140 321.140 0.860 ;
        RECT 322.300 0.140 325.620 0.860 ;
        RECT 326.780 0.140 330.100 0.860 ;
        RECT 331.260 0.140 334.580 0.860 ;
        RECT 335.740 0.140 339.060 0.860 ;
        RECT 340.220 0.140 343.540 0.860 ;
        RECT 344.700 0.140 348.020 0.860 ;
        RECT 349.180 0.140 352.500 0.860 ;
        RECT 353.660 0.140 356.980 0.860 ;
        RECT 358.140 0.140 361.460 0.860 ;
        RECT 362.620 0.140 365.940 0.860 ;
        RECT 367.100 0.140 370.420 0.860 ;
        RECT 371.580 0.140 374.900 0.860 ;
        RECT 376.060 0.140 379.380 0.860 ;
        RECT 380.540 0.140 383.860 0.860 ;
        RECT 385.020 0.140 388.340 0.860 ;
        RECT 389.500 0.140 392.820 0.860 ;
        RECT 393.980 0.140 397.300 0.860 ;
        RECT 398.460 0.140 401.780 0.860 ;
        RECT 402.940 0.140 406.260 0.860 ;
        RECT 407.420 0.140 410.740 0.860 ;
        RECT 411.900 0.140 415.220 0.860 ;
        RECT 416.380 0.140 419.700 0.860 ;
        RECT 420.860 0.140 424.180 0.860 ;
        RECT 425.340 0.140 428.660 0.860 ;
        RECT 429.820 0.140 433.140 0.860 ;
        RECT 434.300 0.140 437.620 0.860 ;
        RECT 438.780 0.140 442.100 0.860 ;
        RECT 443.260 0.140 446.580 0.860 ;
        RECT 447.740 0.140 451.060 0.860 ;
        RECT 452.220 0.140 455.540 0.860 ;
        RECT 456.700 0.140 460.020 0.860 ;
        RECT 461.180 0.140 464.500 0.860 ;
        RECT 465.660 0.140 468.980 0.860 ;
        RECT 470.140 0.140 473.460 0.860 ;
        RECT 474.620 0.140 477.940 0.860 ;
        RECT 479.100 0.140 482.420 0.860 ;
        RECT 483.580 0.140 486.900 0.860 ;
        RECT 488.060 0.140 491.380 0.860 ;
        RECT 492.540 0.140 495.860 0.860 ;
        RECT 497.020 0.140 500.340 0.860 ;
        RECT 501.500 0.140 504.820 0.860 ;
        RECT 505.980 0.140 509.300 0.860 ;
        RECT 510.460 0.140 513.780 0.860 ;
        RECT 514.940 0.140 518.260 0.860 ;
        RECT 519.420 0.140 522.740 0.860 ;
        RECT 523.900 0.140 527.220 0.860 ;
        RECT 528.380 0.140 531.700 0.860 ;
        RECT 532.860 0.140 536.180 0.860 ;
        RECT 537.340 0.140 540.660 0.860 ;
        RECT 541.820 0.140 545.140 0.860 ;
        RECT 546.300 0.140 549.620 0.860 ;
        RECT 550.780 0.140 554.100 0.860 ;
        RECT 555.260 0.140 558.580 0.860 ;
        RECT 559.740 0.140 563.060 0.860 ;
        RECT 564.220 0.140 567.540 0.860 ;
        RECT 568.700 0.140 572.020 0.860 ;
        RECT 573.180 0.140 576.500 0.860 ;
        RECT 577.660 0.140 580.980 0.860 ;
        RECT 582.140 0.140 585.460 0.860 ;
        RECT 586.620 0.140 589.940 0.860 ;
        RECT 591.100 0.140 594.420 0.860 ;
        RECT 595.580 0.140 598.900 0.860 ;
        RECT 600.060 0.140 603.380 0.860 ;
        RECT 604.540 0.140 607.860 0.860 ;
        RECT 609.020 0.140 612.340 0.860 ;
        RECT 613.500 0.140 616.820 0.860 ;
        RECT 617.980 0.140 621.300 0.860 ;
      LAYER Metal3 ;
        RECT 16.010 0.700 622.070 74.900 ;
  END
END dac_logic
END LIBRARY

